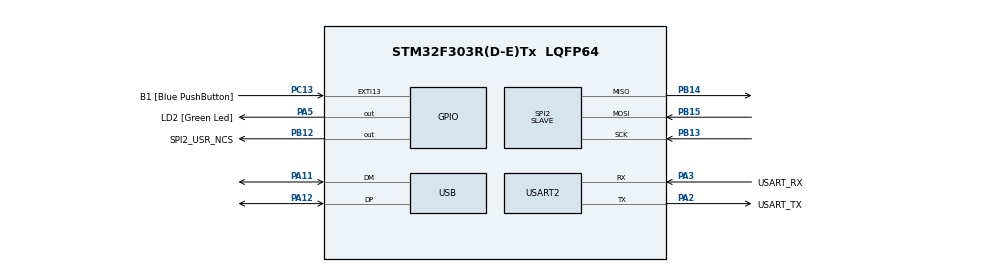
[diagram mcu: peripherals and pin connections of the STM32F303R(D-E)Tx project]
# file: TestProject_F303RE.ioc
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Mcu.Family=STM32F3
Mcu.Name=STM32F303R(D-E)Tx
Mcu.Package=LQFP64
NVIC.PriorityGroup=NVIC_PRIORITYGROUP_0
NVIC.USB_LP_CAN_RX0_IRQn=true\:0\:0\:false\:false\:true\:false\:true
PA11.Mode=Device
PA11.Signal=USB_DM
PA12.Mode=Device
PA12.Signal=USB_DP
PA13.GPIO_Label=TMS
PA13.Mode=Serial_Wire
PA13.Signal=SYS_JTMS-SWDIO
PA14.GPIO_Label=TCK
PA14.Mode=Serial_Wire
PA14.Signal=SYS_JTCK-SWCLK
PA2.GPIO_Label=USART_TX
PA2.GPIO_Mode=GPIO_MODE_AF_PP
PA2.GPIO_PuPd=GPIO_NOPULL
PA2.GPIO_Speed=GPIO_SPEED_FREQ_LOW
PA2.Mode=Asynchronous
PA2.Signal=USART2_TX
PA3.GPIO_Label=USART_RX
PA3.GPIO_Mode=GPIO_MODE_AF_PP
PA3.GPIO_PuPd=GPIO_NOPULL
PA3.GPIO_Speed=GPIO_SPEED_FREQ_LOW
PA3.Mode=Asynchronous
PA3.Signal=USART2_RX
PA5.GPIO_Label=LD2 [Green Led]
PA5.GPIO_Mode=GPIO_MODE_OUTPUT_PP
PA5.GPIO_PuPd=GPIO_NOPULL
PA5.GPIO_Speed=GPIO_SPEED_FREQ_LOW
PA5.Signal=GPIO_Output
PB12.GPIO_Label=SPI2_USR_NCS
PB12.GPIO_PuPd=GPIO_PULLUP
PB12.GPIO_Speed=GPIO_SPEED_FREQ_HIGH
PB12.PinState=GPIO_PIN_SET
PB12.Signal=GPIO_Output
PB13.Mode=Full_Duplex_Slave
PB13.Signal=SPI2_SCK
PB14.Mode=Full_Duplex_Slave
PB14.Signal=SPI2_MISO
PB15.Mode=Full_Duplex_Slave
PB15.Signal=SPI2_MOSI
PB3.GPIO_Label=SWO
PB3.Signal=SYS_JTDO-TRACESWO
PC13.GPIO_Label=B1 [Blue PushButton]
PC13.GPIO_ModeDefaultEXTI=GPIO_MODE_IT_FALLING
PC13.Signal=GPXTI13
PC14-OSC32_IN.Mode=LSE-External-Oscillator
PC14-OSC32_IN.Signal=RCC_OSC32_IN
PC15-OSC32_OUT.Mode=LSE-External-Oscillator
PC15-OSC32_OUT.Signal=RCC_OSC32_OUT
PF0-OSC_IN.Mode=HSE-External-Clock-Source
PF0-OSC_IN.Signal=RCC_OSC_IN
PF1-OSC_OUT.Signal=RCC_OSC_OUT
ProjectManager.HeapSize=0x200
ProjectManager.StackSize=0x400
ProjectManager.TargetToolchain=STM32CubeIDE
RCC.AHBFreq_Value=48000000
RCC.APB1CLKDivider=RCC_HCLK_DIV2
RCC.APB1Freq_Value=24000000
RCC.APB1TimFreq_Value=48000000
RCC.APB2Freq_Value=48000000
RCC.APB2TimFreq_Value=48000000
RCC.CortexFreq_Value=48000000
RCC.HCLKFreq_Value=48000000
RCC.HSE_VALUE=8000000
RCC.HSI_VALUE=8000000
RCC.PLLM=8
RCC.PLLMUL=RCC_PLL_MUL6
RCC.PLLN=336
RCC.PLLP=RCC_PLLP_DIV4
RCC.PLLQ=7
RCC.RCC_PLLsource_Clock_Source_FROM_HSE=RCC_HSE_PREDIV_DIV2
RCC.SYSCLKFreq_VALUE=48000000
RCC.SYSCLKSourceVirtual=RCC_SYSCLKSOURCE_PLLCLK
RCC.USBFreq_Value=48000000
SPI2.DataSize=SPI_DATASIZE_8BIT
SPI2.Direction=SPI_DIRECTION_2LINES
SPI2.Mode=SPI_MODE_SLAVE
SPI2.VirtualType=VM_SLAVE
USART2.VirtualMode-Asynchronous=VM_ASYNC
USB_DEVICE.CLASS_NAME_FS=AUDIO
USB_DEVICE.USBD_AUDIO_FREQ=44100
USB_DEVICE.VirtualMode=Audio
USB_DEVICE.VirtualModeFS=Audio_FS
VP_USB_DEVICE_VS_USB_DEVICE_AUDIO_FS.Mode=AUDIO_FS
board=NUCLEO-F303RE

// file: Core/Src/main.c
/* USER CODE BEGIN Header */
/**
  ******************************************************************************
  * @file           : main.c
  * @brief          : Main program body
  ******************************************************************************
  * @attention
  *
  * <h2><center>&copy; Copyright (c) 2020 STMicroelectronics.
  * All rights reserved.</center></h2>
  *
  * This software component is licensed by ST under BSD 3-Clause license,
  * the "License"; You may not use this file except in compliance with the
  * License. You may obtain a copy of the License at:
  *                        opensource.org/licenses/BSD-3-Clause
  *
  ******************************************************************************
  */
/* USER CODE END Header */

#include "main.h"

SPI_HandleTypeDef hspi2;

UART_HandleTypeDef huart2;

void SystemClock_Config(void);
static void MX_GPIO_Init(void);
static void MX_USART2_UART_Init(void);
static void MX_SPI2_Init(void);

int main(void)
{

  /* MCU Configuration--------------------------------------------------------*/

  /* Reset of all peripherals, Initializes the Flash interface and the Systick. */
  HAL_Init();

  /* Configure the system clock */
  SystemClock_Config();

  /* Initialize all configured peripherals */
  MX_GPIO_Init();
  MX_USART2_UART_Init();
  MX_SPI2_Init();

  /* Infinite loop */
  while (1)
  {

  }
}

void SystemClock_Config(void)
{
  RCC_OscInitTypeDef RCC_OscInitStruct = {0};
  RCC_ClkInitTypeDef RCC_ClkInitStruct = {0};
  RCC_PeriphCLKInitTypeDef PeriphClkInit = {0};

  /** Initializes the CPU, AHB and APB busses clocks
  */
  RCC_OscInitStruct.OscillatorType = RCC_OSCILLATORTYPE_HSI;
  RCC_OscInitStruct.HSIState = RCC_HSI_ON;
  RCC_OscInitStruct.HSICalibrationValue = RCC_HSICALIBRATION_DEFAULT;
  RCC_OscInitStruct.PLL.PLLState = RCC_PLL_ON;
  RCC_OscInitStruct.PLL.PLLSource = RCC_PLLSOURCE_HSI;
  RCC_OscInitStruct.PLL.PLLMUL = RCC_PLL_MUL9;
  RCC_OscInitStruct.PLL.PREDIV = RCC_PREDIV_DIV1;
  if (HAL_RCC_OscConfig(&RCC_OscInitStruct) != HAL_OK)
  {
    Error_Handler();
  }
  /** Initializes the CPU, AHB and APB busses clocks
  */
  RCC_ClkInitStruct.ClockType = RCC_CLOCKTYPE_HCLK|RCC_CLOCKTYPE_SYSCLK
                              |RCC_CLOCKTYPE_PCLK1|RCC_CLOCKTYPE_PCLK2;
  RCC_ClkInitStruct.SYSCLKSource = RCC_SYSCLKSOURCE_PLLCLK;
  RCC_ClkInitStruct.AHBCLKDivider = RCC_SYSCLK_DIV1;
  RCC_ClkInitStruct.APB1CLKDivider = RCC_HCLK_DIV2;
  RCC_ClkInitStruct.APB2CLKDivider = RCC_HCLK_DIV1;

  if (HAL_RCC_ClockConfig(&RCC_ClkInitStruct, FLASH_LATENCY_2) != HAL_OK)
  {
    Error_Handler();
  }
  PeriphClkInit.PeriphClockSelection = RCC_PERIPHCLK_USART2;
  PeriphClkInit.Usart2ClockSelection = RCC_USART2CLKSOURCE_PCLK1;
  if (HAL_RCCEx_PeriphCLKConfig(&PeriphClkInit) != HAL_OK)
  {
    Error_Handler();
  }
}

static void MX_SPI2_Init(void)
{

  /* SPI2 parameter configuration*/
  hspi2.Instance = SPI2;
  hspi2.Init.Mode = SPI_MODE_MASTER;
  hspi2.Init.Direction = SPI_DIRECTION_2LINES;
  hspi2.Init.DataSize = SPI_DATASIZE_4BIT;
  hspi2.Init.CLKPolarity = SPI_POLARITY_LOW;
  hspi2.Init.CLKPhase = SPI_PHASE_1EDGE;
  hspi2.Init.NSS = SPI_NSS_HARD_OUTPUT;
  hspi2.Init.BaudRatePrescaler = SPI_BAUDRATEPRESCALER_16;
  hspi2.Init.FirstBit = SPI_FIRSTBIT_MSB;
  hspi2.Init.TIMode = SPI_TIMODE_DISABLE;
  hspi2.Init.CRCCalculation = SPI_CRCCALCULATION_DISABLE;
  hspi2.Init.CRCPolynomial = 7;
  hspi2.Init.CRCLength = SPI_CRC_LENGTH_DATASIZE;
  hspi2.Init.NSSPMode = SPI_NSS_PULSE_ENABLE;
  if (HAL_SPI_Init(&hspi2) != HAL_OK)
  {
    Error_Handler();
  }

}

static void MX_USART2_UART_Init(void)
{

  huart2.Instance = USART2;
  huart2.Init.BaudRate = 38400;
  huart2.Init.WordLength = UART_WORDLENGTH_8B;
  huart2.Init.StopBits = UART_STOPBITS_1;
  huart2.Init.Parity = UART_PARITY_NONE;
  huart2.Init.Mode = UART_MODE_TX_RX;
  huart2.Init.HwFlowCtl = UART_HWCONTROL_NONE;
  huart2.Init.OverSampling = UART_OVERSAMPLING_16;
  huart2.Init.OneBitSampling = UART_ONE_BIT_SAMPLE_DISABLE;
  huart2.AdvancedInit.AdvFeatureInit = UART_ADVFEATURE_NO_INIT;
  if (HAL_UART_Init(&huart2) != HAL_OK)
  {
    Error_Handler();
  }

}

static void MX_GPIO_Init(void)
{
  GPIO_InitTypeDef GPIO_InitStruct = {0};

  /* GPIO Ports Clock Enable */
  __HAL_RCC_GPIOC_CLK_ENABLE();
  __HAL_RCC_GPIOF_CLK_ENABLE();
  __HAL_RCC_GPIOA_CLK_ENABLE();
  __HAL_RCC_GPIOB_CLK_ENABLE();

  /*Configure GPIO pin Output Level */
  HAL_GPIO_WritePin(LD2_GPIO_Port, LD2_Pin, GPIO_PIN_RESET);

  /*Configure GPIO pin : B1_Pin */
  GPIO_InitStruct.Pin = B1_Pin;
  GPIO_InitStruct.Mode = GPIO_MODE_IT_FALLING;
  GPIO_InitStruct.Pull = GPIO_NOPULL;
  HAL_GPIO_Init(B1_GPIO_Port, &GPIO_InitStruct);

  /*Configure GPIO pin : LD2_Pin */
  GPIO_InitStruct.Pin = LD2_Pin;
  GPIO_InitStruct.Mode = GPIO_MODE_OUTPUT_PP;
  GPIO_InitStruct.Pull = GPIO_NOPULL;
  GPIO_InitStruct.Speed = GPIO_SPEED_FREQ_LOW;
  HAL_GPIO_Init(LD2_GPIO_Port, &GPIO_InitStruct);

}

void Error_Handler(void)
{
}

/************************ (C) COPYRIGHT STMicroelectronics *****END OF FILE****/
